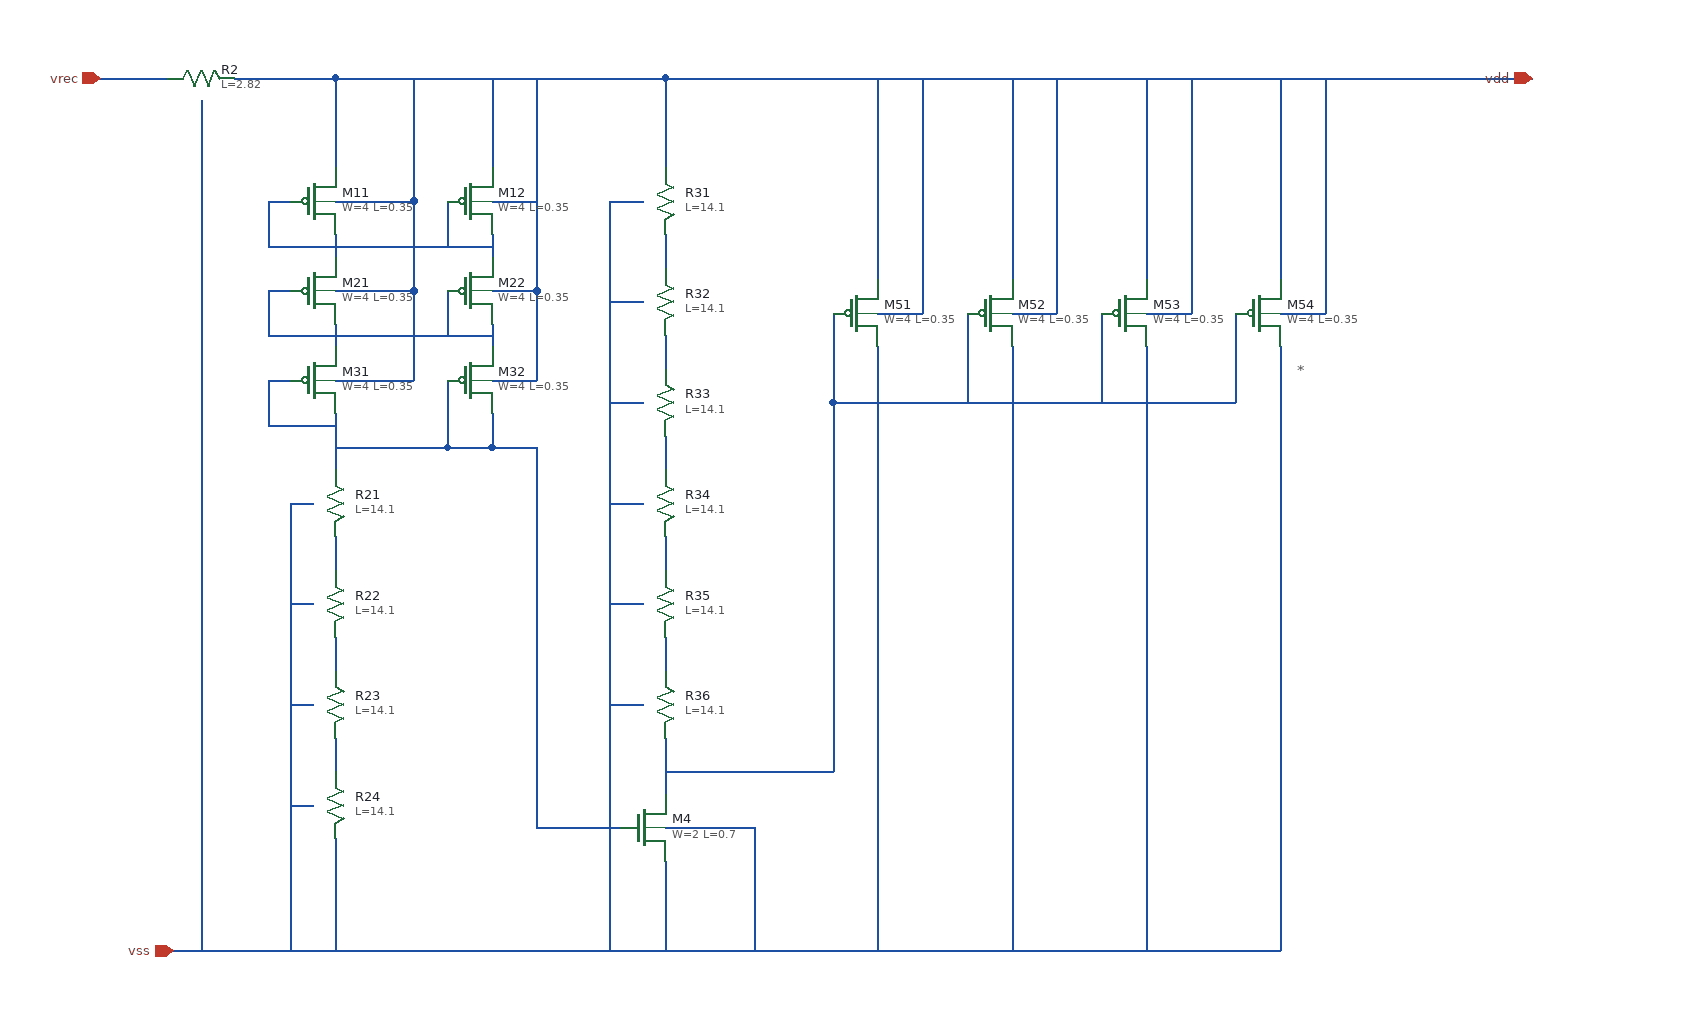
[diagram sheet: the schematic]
v {xschem version=3.1.0 file_version=1.2
}
G {}
K {}
V {}
S {}
E {}
T {*} 1170 -640 0 0 0.4 0.4 {}
N 100 -890 160 -890 {
lab=vrec}
N 220 -890 310 -890 {
lab=vdd}
N 310 -890 510 -890 {
lab=vdd}
N 605 -890 755 -890 {
lab=vdd}
N 795 -680 835 -680 {
lab=vdd}
N 310 -750 310 -730 {
lab=#net1}
N 310 -670 310 -650 {
lab=#net2}
N 250 -780 270 -780 {
lab=#net1}
N 250 -780 250 -740 {
lab=#net1}
N 250 -740 310 -740 {
lab=#net1}
N 250 -700 270 -700 {
lab=#net2}
N 250 -700 250 -660 {
lab=#net2}
N 250 -660 310 -660 {
lab=#net2}
N 250 -620 270 -620 {
lab=#net3}
N 250 -620 250 -580 {
lab=#net3}
N 250 -580 310 -580 {
lab=#net3}
N 310 -780 380 -780 {
lab=vdd}
N 310 -700 380 -700 {
lab=vdd}
N 380 -780 380 -700 {
lab=vdd}
N 310 -620 380 -620 {
lab=vdd}
N 380 -700 380 -620 {
lab=vdd}
N 310 -590 310 -540 {
lab=#net3}
N 165 -110 375 -110 {
lab=vss}
N 310 -480 310 -450 {
lab=#net4}
N 605 -190 605 -110 {
lab=vss}
N 375 -110 575 -110 {
lab=vss}
N 670 -110 820 -110 {
lab=vss}
N 605 -220 685 -220 {
lab=vss}
N 685 -220 685 -110 {
lab=vss}
N 310 -560 410 -560 {
lab=#net3}
N 270 -510 290 -510 {
lab=vss}
N 310 -890 310 -810 {
lab=vdd}
N 380 -890 380 -780 {
lab=vdd}
N 795 -650 795 -450 {
lab=vss}
N 795 -890 795 -710 {
lab=vdd}
N 835 -890 835 -680 {
lab=vdd}
N 820 -110 1010 -110 {
lab=vss}
N 450 -890 450 -810 {
lab=vdd}
N 450 -750 450 -730 {
lab=#net1}
N 450 -670 450 -650 {
lab=#net2}
N 450 -590 450 -560 {
lab=#net3}
N 410 -620 410 -560 {
lab=#net3}
N 310 -660 450 -660 {
lab=#net2}
N 310 -740 450 -740 {
lab=#net1}
N 410 -780 410 -740 {
lab=#net1}
N 410 -700 410 -660 {
lab=#net2}
N 450 -700 490 -700 {
lab=vdd}
N 490 -890 490 -700 {
lab=vdd}
N 450 -780 490 -780 {
lab=vdd}
N 450 -620 490 -620 {
lab=vdd}
N 490 -700 490 -620 {
lab=vdd}
N 575 -110 670 -110 {
lab=vss}
N 915 -890 915 -710 {
lab=vdd}
N 1035 -890 1035 -710 {
lab=vdd}
N 1155 -890 1155 -710 {
lab=vdd}
N 915 -680 955 -680 {
lab=vdd}
N 1035 -680 1075 -680 {
lab=vdd}
N 1155 -680 1195 -680 {
lab=vdd}
N 955 -890 955 -680 {
lab=vdd}
N 1075 -890 1075 -680 {
lab=vdd}
N 1195 -890 1195 -680 {
lab=vdd}
N 915 -650 915 -450 {
lab=vss}
N 1035 -650 1035 -450 {
lab=#net5}
N 1155 -650 1155 -450 {
lab=#net6}
N 510 -890 605 -890 {
lab=vdd}
N 1115 -680 1115 -600 {
lab=#net7}
N 995 -680 995 -600 {
lab=#net7}
N 875 -680 875 -600 {
lab=#net7}
N 755 -680 755 -600 {
lab=#net7}
N 310 -390 310 -360 {
lab=#net8}
N 270 -420 290 -420 {
lab=vss}
N 310 -300 310 -270 {
lab=#net9}
N 270 -330 290 -330 {
lab=vss}
N 270 -240 290 -240 {
lab=vss}
N 605 -390 605 -360 {
lab=#net10}
N 605 -480 605 -450 {
lab=#net11}
N 605 -570 605 -540 {
lab=#net12}
N 605 -660 605 -630 {
lab=#net13}
N 605 -750 605 -720 {
lab=#net14}
N 605 -890 605 -810 {
lab=vdd}
N 605 -300 605 -250 {
lab=#net7}
N 310 -210 310 -110 {
lab=vss}
N 795 -450 795 -110 {
lab=vss}
N 915 -450 915 -110 {
lab=vss}
N 1035 -450 1035 -110 {
lab=#net5}
N 1155 -450 1155 -110 {
lab=#net6}
N 755 -890 1380 -890 {
lab=vdd}
N 755 -600 1115 -600 {
lab=#net7}
N 410 -560 450 -560 {
lab=#net3}
N 490 -220 565 -220 {
lab=#net3}
N 490 -560 490 -220 {
lab=#net3}
N 450 -560 490 -560 {
lab=#net3}
N 605 -270 755 -270 {
lab=#net7}
N 755 -600 755 -270 {
lab=#net7}
N 270 -510 270 -110 {
lab=vss}
N 555 -780 585 -780 {
lab=vss}
N 555 -690 585 -690 {
lab=vss}
N 555 -600 585 -600 {
lab=vss}
N 555 -510 585 -510 {
lab=vss}
N 555 -420 585 -420 {
lab=vss}
N 555 -330 585 -330 {
lab=vss}
N 555 -780 555 -110 {
lab=vss}
N 190 -870 190 -110 {
lab=vss}
N 1010 -110 1155 -110 {}
C {devices/iopin.sym} 165 -110 2 0 {name=p3 lab=vss}
C {sky130_fd_pr/nfet_01v8_lvt.sym} 585 -220 0 0 {name=M4
L=0.7
W=2
nf=1
mult=1
ad="'int((nf+1)/2) * W/nf * 0.29'" 
pd="'2*int((nf+1)/2) * (W/nf + 0.29)'"
as="'int((nf+2)/2) * W/nf * 0.29'" 
ps="'2*int((nf+2)/2) * (W/nf + 0.29)'"
nrd="'0.29 / W'" nrs="'0.29 / W'"
sa=0 sb=0 sd=0
model=nfet_01v8_lvt
spiceprefix=X
}
C {sky130_fd_pr/pfet_01v8_lvt.sym} 775 -680 0 0 {name=M51
L=0.35
W=4
nf=1
mult=1
ad="'int((nf+1)/2) * W/nf * 0.29'" 
pd="'2*int((nf+1)/2) * (W/nf + 0.29)'"
as="'int((nf+2)/2) * W/nf * 0.29'" 
ps="'2*int((nf+2)/2) * (W/nf + 0.29)'"
nrd="'0.29 / W'" nrs="'0.29 / W'"
sa=0 sb=0 sd=0
model=pfet_01v8_lvt
spiceprefix=X
}
C {sky130_fd_pr/pfet_01v8_lvt.sym} 290 -780 0 0 {name=M11
L=0.35
W=4
nf=1
mult=1
ad="'int((nf+1)/2) * W/nf * 0.29'" 
pd="'2*int((nf+1)/2) * (W/nf + 0.29)'"
as="'int((nf+2)/2) * W/nf * 0.29'" 
ps="'2*int((nf+2)/2) * (W/nf + 0.29)'"
nrd="'0.29 / W'" nrs="'0.29 / W'"
sa=0 sb=0 sd=0
model=pfet_01v8_lvt
spiceprefix=X
}
C {sky130_fd_pr/pfet_01v8_lvt.sym} 290 -700 0 0 {name=M21
L=0.35
W=4
nf=1
mult=1
ad="'int((nf+1)/2) * W/nf * 0.29'" 
pd="'2*int((nf+1)/2) * (W/nf + 0.29)'"
as="'int((nf+2)/2) * W/nf * 0.29'" 
ps="'2*int((nf+2)/2) * (W/nf + 0.29)'"
nrd="'0.29 / W'" nrs="'0.29 / W'"
sa=0 sb=0 sd=0
model=pfet_01v8_lvt
spiceprefix=X
}
C {sky130_fd_pr/pfet_01v8_lvt.sym} 290 -620 0 0 {name=M31
L=0.35
W=4
nf=1
mult=1
ad="'int((nf+1)/2) * W/nf * 0.29'" 
pd="'2*int((nf+1)/2) * (W/nf + 0.29)'"
as="'int((nf+2)/2) * W/nf * 0.29'" 
ps="'2*int((nf+2)/2) * (W/nf + 0.29)'"
nrd="'0.29 / W'" nrs="'0.29 / W'"
sa=0 sb=0 sd=0
model=pfet_01v8_lvt
spiceprefix=X
}
C {devices/iopin.sym} 100 -890 2 0 {name=p4 lab=vrec}
C {devices/iopin.sym} 1380 -890 0 0 {name=p2 lab=vdd}
C {sky130_fd_pr/pfet_01v8_lvt.sym} 430 -780 0 0 {name=M12
L=0.35
W=4
nf=1
mult=1
ad="'int((nf+1)/2) * W/nf * 0.29'" 
pd="'2*int((nf+1)/2) * (W/nf + 0.29)'"
as="'int((nf+2)/2) * W/nf * 0.29'" 
ps="'2*int((nf+2)/2) * (W/nf + 0.29)'"
nrd="'0.29 / W'" nrs="'0.29 / W'"
sa=0 sb=0 sd=0
model=pfet_01v8_lvt
spiceprefix=X
}
C {sky130_fd_pr/pfet_01v8_lvt.sym} 430 -700 0 0 {name=M22
L=0.35
W=4
nf=1
mult=1
ad="'int((nf+1)/2) * W/nf * 0.29'" 
pd="'2*int((nf+1)/2) * (W/nf + 0.29)'"
as="'int((nf+2)/2) * W/nf * 0.29'" 
ps="'2*int((nf+2)/2) * (W/nf + 0.29)'"
nrd="'0.29 / W'" nrs="'0.29 / W'"
sa=0 sb=0 sd=0
model=pfet_01v8_lvt
spiceprefix=X
}
C {sky130_fd_pr/pfet_01v8_lvt.sym} 430 -620 0 0 {name=M32
L=0.35
W=4
nf=1
mult=1
ad="'int((nf+1)/2) * W/nf * 0.29'" 
pd="'2*int((nf+1)/2) * (W/nf + 0.29)'"
as="'int((nf+2)/2) * W/nf * 0.29'" 
ps="'2*int((nf+2)/2) * (W/nf + 0.29)'"
nrd="'0.29 / W'" nrs="'0.29 / W'"
sa=0 sb=0 sd=0
model=pfet_01v8_lvt
spiceprefix=X
}
C {sky130_fd_pr/pfet_01v8_lvt.sym} 895 -680 0 0 {name=M52
L=0.35
W=4
nf=1
mult=1
ad="'int((nf+1)/2) * W/nf * 0.29'" 
pd="'2*int((nf+1)/2) * (W/nf + 0.29)'"
as="'int((nf+2)/2) * W/nf * 0.29'" 
ps="'2*int((nf+2)/2) * (W/nf + 0.29)'"
nrd="'0.29 / W'" nrs="'0.29 / W'"
sa=0 sb=0 sd=0
model=pfet_01v8_lvt
spiceprefix=X
}
C {sky130_fd_pr/pfet_01v8_lvt.sym} 1015 -680 0 0 {name=M53
L=0.35
W=4
nf=1
mult=1
ad="'int((nf+1)/2) * W/nf * 0.29'" 
pd="'2*int((nf+1)/2) * (W/nf + 0.29)'"
as="'int((nf+2)/2) * W/nf * 0.29'" 
ps="'2*int((nf+2)/2) * (W/nf + 0.29)'"
nrd="'0.29 / W'" nrs="'0.29 / W'"
sa=0 sb=0 sd=0
model=pfet_01v8_lvt
spiceprefix=X
}
C {sky130_fd_pr/pfet_01v8_lvt.sym} 1135 -680 0 0 {name=M54
L=0.35
W=4
nf=1
mult=1
ad="'int((nf+1)/2) * W/nf * 0.29'" 
pd="'2*int((nf+1)/2) * (W/nf + 0.29)'"
as="'int((nf+2)/2) * W/nf * 0.29'" 
ps="'2*int((nf+2)/2) * (W/nf + 0.29)'"
nrd="'0.29 / W'" nrs="'0.29 / W'"
sa=0 sb=0 sd=0
model=pfet_01v8_lvt
spiceprefix=X
}
C {sky130_fd_pr/res_xhigh_po_1p41.sym} 310 -510 0 0 {name=R21
L=14.1
model=res_xhigh_po_1p41
spiceprefix=X
mult=1}
C {sky130_fd_pr/res_xhigh_po_1p41.sym} 310 -420 0 0 {name=R22
L=14.1
model=res_xhigh_po_1p41
spiceprefix=X
mult=1}
C {sky130_fd_pr/res_xhigh_po_1p41.sym} 310 -330 0 0 {name=R23
L=14.1
model=res_xhigh_po_1p41
spiceprefix=X
mult=1}
C {sky130_fd_pr/res_xhigh_po_1p41.sym} 310 -240 0 0 {name=R24
L=14.1
model=res_xhigh_po_1p41
spiceprefix=X
mult=1}
C {sky130_fd_pr/res_xhigh_po_1p41.sym} 605 -780 0 0 {name=R31
L=14.1
model=res_xhigh_po_1p41
spiceprefix=X
mult=1}
C {sky130_fd_pr/res_xhigh_po_1p41.sym} 605 -690 0 0 {name=R32
L=14.1
model=res_xhigh_po_1p41
spiceprefix=X
mult=1}
C {sky130_fd_pr/res_xhigh_po_1p41.sym} 605 -600 0 0 {name=R33
L=14.1
model=res_xhigh_po_1p41
spiceprefix=X
mult=1}
C {sky130_fd_pr/res_xhigh_po_1p41.sym} 605 -510 0 0 {name=R34
L=14.1
model=res_xhigh_po_1p41
spiceprefix=X
mult=1}
C {sky130_fd_pr/res_xhigh_po_1p41.sym} 605 -420 0 0 {name=R35
L=14.1
model=res_xhigh_po_1p41
spiceprefix=X
mult=1}
C {sky130_fd_pr/res_xhigh_po_1p41.sym} 605 -330 0 0 {name=R36
L=14.1
model=res_xhigh_po_1p41
spiceprefix=X
mult=1}
C {sky130_fd_pr/res_xhigh_po_1p41.sym} 190 -890 3 0 {name=R2
L=2.82
model=res_xhigh_po_1p41
spiceprefix=X
mult=1}
